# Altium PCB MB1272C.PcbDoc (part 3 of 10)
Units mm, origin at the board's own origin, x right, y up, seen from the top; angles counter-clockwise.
Board outline 101 x 71 mm, 6 copper layers (Top Layer, Signal Layer 1, Signal Layer 2, Signal Layer 3, Signal Layer 4, Bottom Layer), stack 1.552 mm thick; 520 components, 478 nets, 2156 pads, 1894 vias.

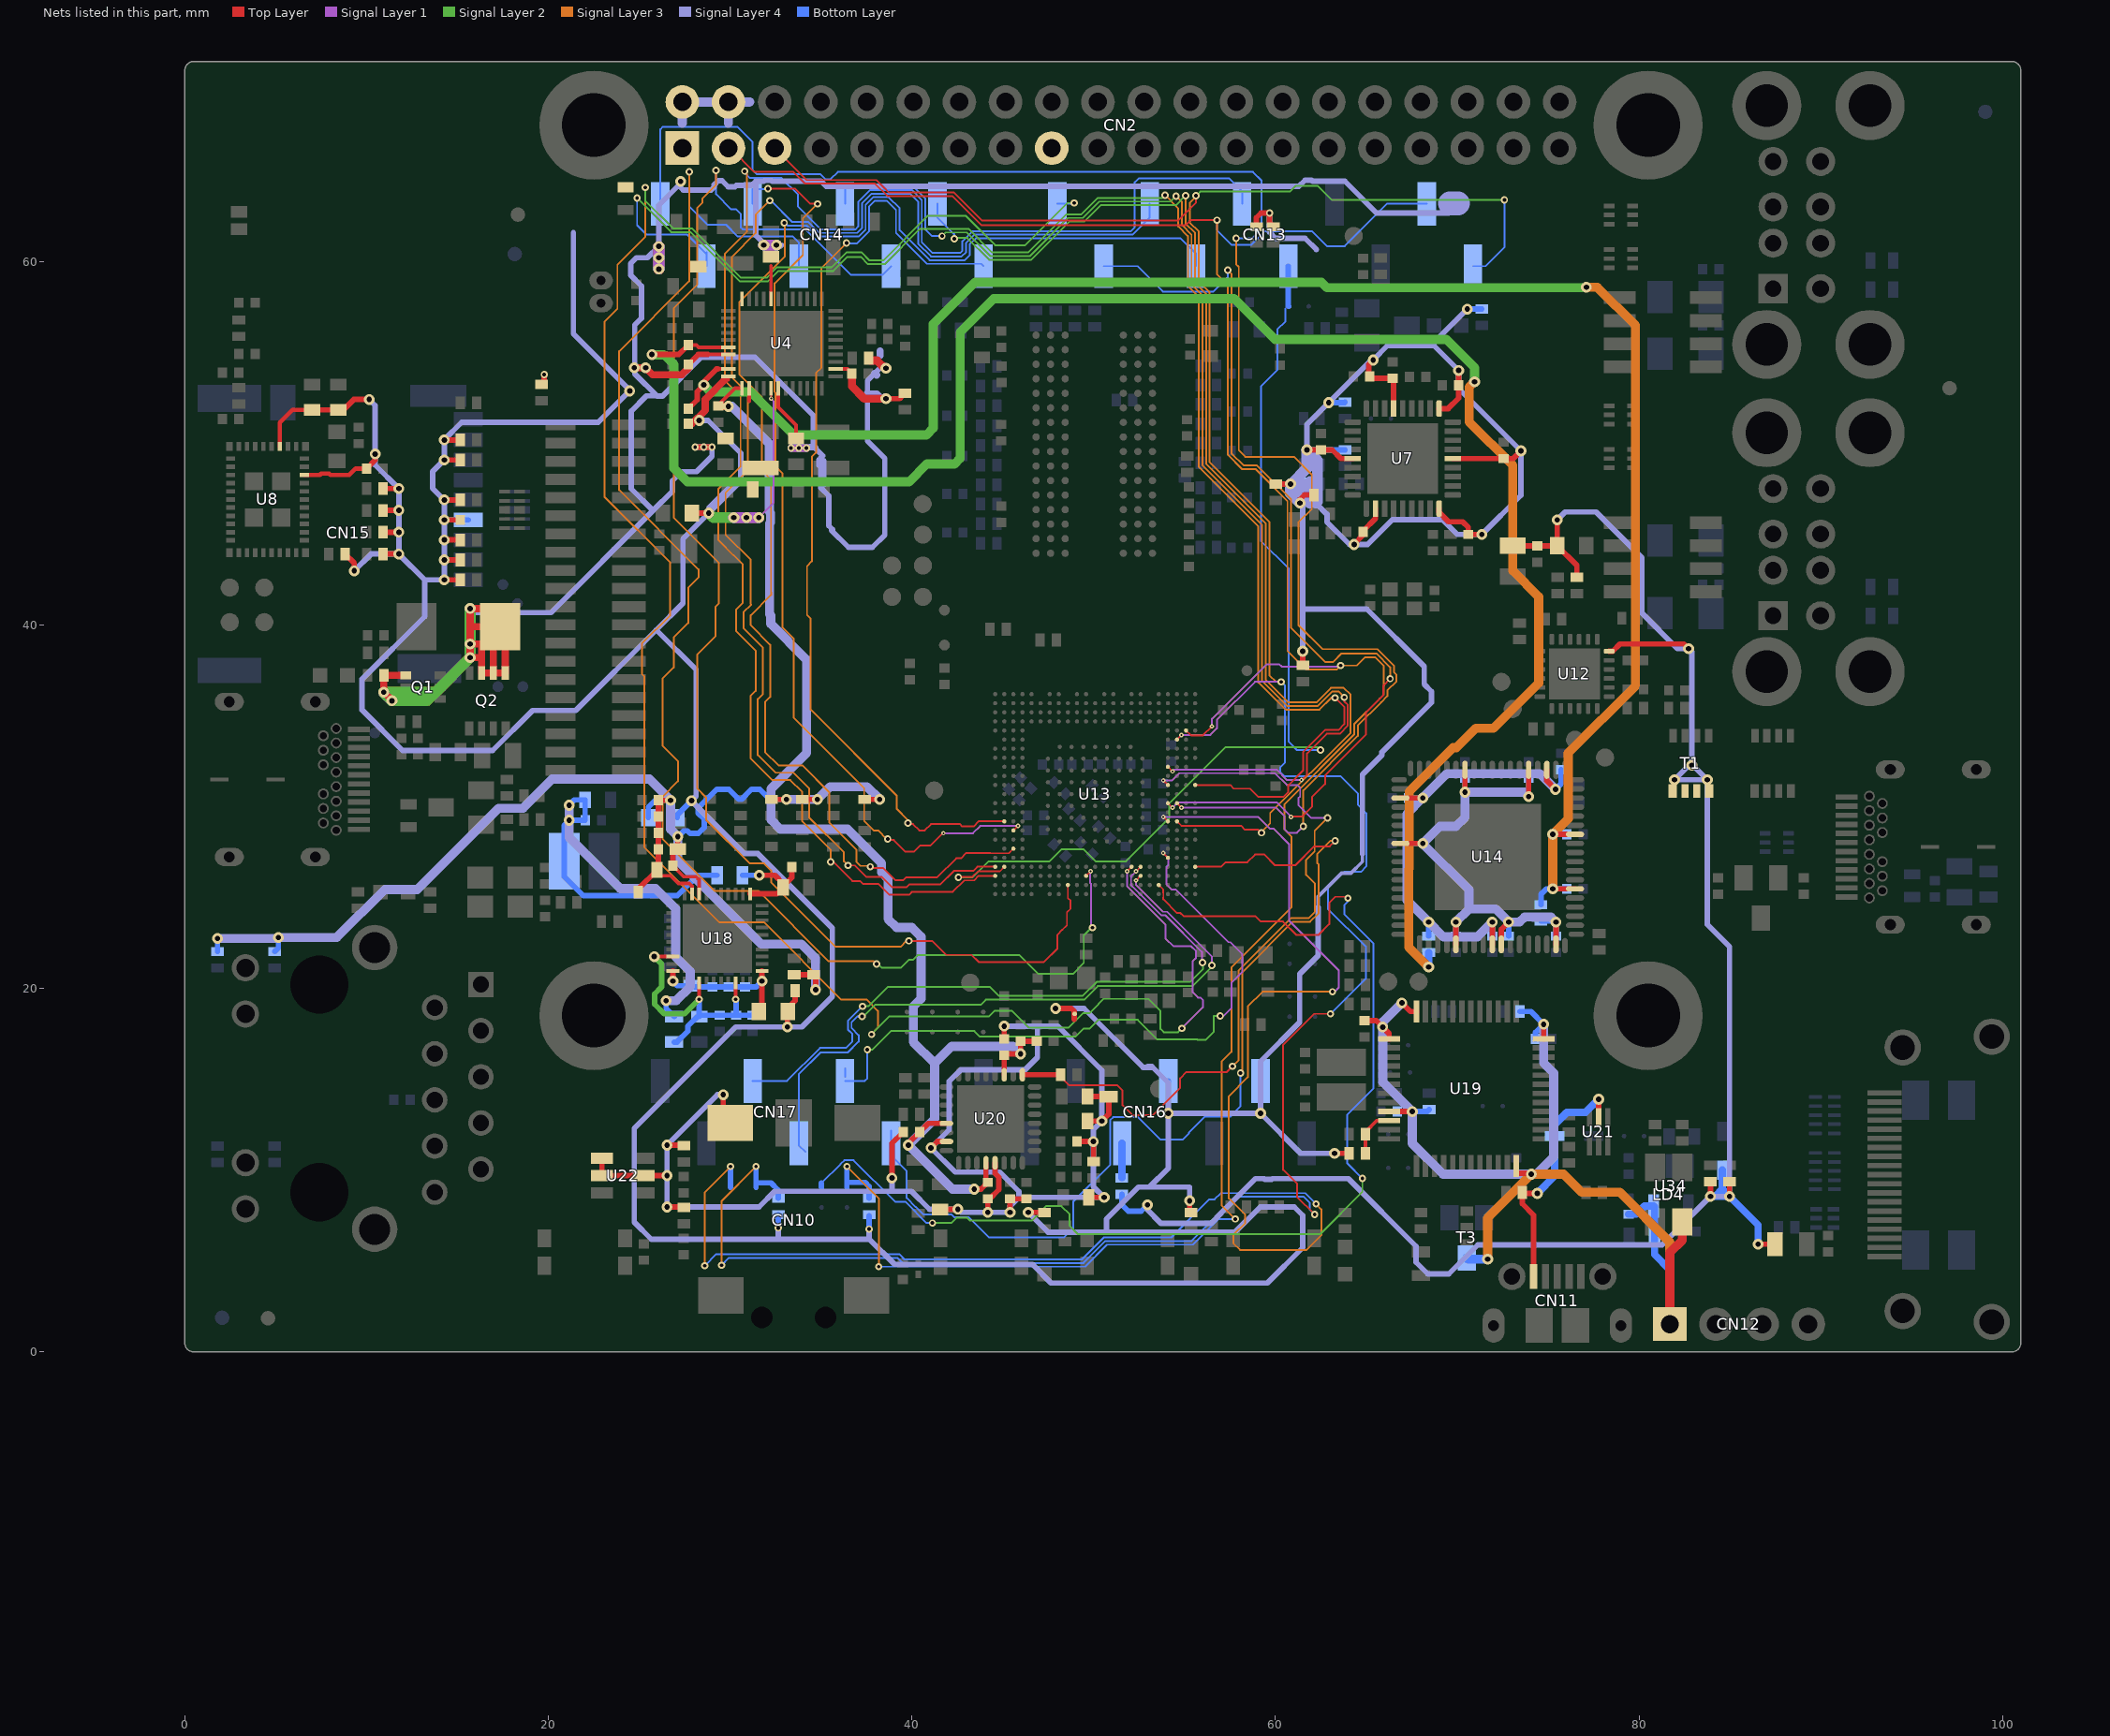
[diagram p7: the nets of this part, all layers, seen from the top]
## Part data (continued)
U7: library part MCD-00145, "USB HUB 2,0 Controller", Manufacturer=MICROCHIP
U8: library part MCD-00268, "IEEE802.11b/g/n W-LAN + Bluetooth 4.1+EDR module", Manufacturer=MURATA
U10 U26: library part MCD-00667, "4-line ESD protection for high speed lines", Manufacturer=STMICROELECTRONICS, Package=uQFN-10L
U12: library part MCD-00676, "USB Type-C controller with VCONN switch", Manufacturer=STMICROELECTRONICS, Manufacturer_Part_Number=STUSB1600AQTR
U13: library part MCD-00677, "MPU TFBGA12x12 secure boot+crypto", Manufacturer=STMICROELECTRONICS
U14: library part MCD-00267, "HDMI Transmitter, 72-pin 10 × 10 mm QFN", Manufacturer=LATTICE, Manufacturer_Part_Number=SiI9022ACNU
U15 U17: library part MCD-01125, "DUAL TRANSIL ARRAY FOR ESD PROTECTION", Manufacturer=STMICROELECTRONICS, Manufacturer_Part_Number=ESDA25L, Package=ESD_SOT23
U16 U23 U24 U25 U27 U28 U30: library part MCD-01026, "High power transient voltage suppressor", Manufacturer=STMICROELECTRONICS, Manufacturer_Part_Number=ESDA7P120-1U1M, Package=QFN1610
U18: library part MCD-01130, "10/100/1000M GIGABIT Ethernet Transceiver, QFN40 , SMPS version", Manufacturer=REALTEK
U19: library part MCD-00085, "Medium-density performance line ARM-based 32-bit MCU with 128KB Flash", Manufacturer=STMICROELECTRONICS, Manufacturer_Part_Number=STM32F103CBT6
U20: library part MCD-00265, "Low-Power, Stereo Codec with Headphone Amp", Manufacturer="CIRRUS LOGIC", Manufacturer_Part_Number=CS42L51-CNZ
U21: library part MCD-00169, "USB OTG FS ESD protection", Manufacturer=STMICROELECTRONICS, Manufacturer_Part_Number=USBLC6-2P6
U22: library part MCD-00247, "Quad Bidir ESD protection", Manufacturer=STMICROELECTRONICS, Manufacturer_Part_Number=ESDA6V1BC6
U31 U32: library part MCD-00297, "ESD protection & Common Filter High Speed serial Interfaces", Manufacturer=STMICROELECTRONICS, Manufacturer_Part_Number=ECMF04-4HSWM10
U33: library part MCD-01457, "ESD protection , 5 lines", Manufacturer=STMICROELECTRONICS, Package=QFN
U34: library part MCD-00086, "Ultra low drop-low noise BiCMOS voltage, regulators low ESR capacitors compatible", Manufacturer=STMICROELECTRONICS, Manufacturer_Part_Number=LD3985M33R
U35: library part MCD-00170, "ESD protection 6V1", Manufacturer=STMICROELECTRONICS, Manufacturer_Part_Number=ESDALC6V1-1U2
X1: library part MCD-01036, "Crystal 24MHz, 6pF, +-20ppm, 80ohms max, SMD", Manufacturer=NDK, Manufacturer_Part_Number="NX2016SA 24MHz EXS00A-CS10820", Package="(2016) 2.0 x 1.6 x 0.45 mm"
X2: library part MCD-01463, "Crystal 25Mhz, 10pF, -+50PPM, SMD", Manufacturer=NDK, Manufacturer_Part_Number="NX3225GA 25MHz EXS00A-CG06750", Package=3225
X4: library part MCD-01479, "Crystal 32.768kHz, 6pF, -+20PPM, R=80K, SMD", Manufacturer=NDK, Manufacturer_Part_Number="NX2012SA 32.768KHz EXS00A-MU00527", Package=NX2012SA
X5: library part MCD-00092, "Crystal 8Mhz, 8pF, -+50PPM, SMD", Manufacturer=NDK, Manufacturer_Part_Number="NX3225GD 8MHz EXS00A-CG04874"
X6: library part MCD-01627, "Oscillator 24Mhz, +-50ppm, Vcc:3.3V typ (1.62V min), square wave: [0.1Vcc;0.9Vcc], Enable pin", Manufacturer=NDK, Manufacturer_Part_Number="NZ2016SH 24MHz END4869F", Package=2.0x1.6x0.7mm

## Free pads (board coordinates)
  round 0.508 on Mech16: 1(25.738,-17.565) 1(74.585,-17.565)

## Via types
v1: diameter 0.4, hole 0.2, Top Layer to Bottom Layer, tented both sides, 912 vias
v2: diameter 0.25, hole 0.1, Top Layer to Signal Layer 1, tented top, 493 vias
v3: diameter 0.6, hole 0.3, Top Layer to Bottom Layer, tented both sides, 452 vias
v4: diameter 0.25, hole 0.1, Top Layer to Signal Layer 1, tented both sides, 37 vias

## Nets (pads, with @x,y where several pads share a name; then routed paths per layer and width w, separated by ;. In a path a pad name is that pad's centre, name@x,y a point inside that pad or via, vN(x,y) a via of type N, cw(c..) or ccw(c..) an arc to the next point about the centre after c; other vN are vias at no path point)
1V2_CVCC12: C141.2 C142.2 C164.2 C169.2 C170.2 C172.2 R152.1 U14.5 U14.12 U14.26 U14.42 U14.47 U14.53 | length 32.5
  Top Layer w0.3: U14.26@66.875,27.975 v3(68.1,27.975) ; U14.42@69.925,22.425 v3(69.925,23.65) ; v3(70.425,30.8) U14.12@70.425,32.025 ; U14.47@72.425,22.425 72.425,23.25 v3(72.825,23.65) ; U14.5@73.925,32.025 73.925,30.555 v3(73.929,30.551) v3@73.929,30.521 ; U14.53@75.425,22.425 v3(75.425,23.65)
  Signal Layer 4 w0.5: v3(69.925,23.65) 70.64,24.365 ; v3(73.929,30.551) 73.68,30.8 v3(70.425,30.8) 70.425,29.41 69.93,28.915 69.04,28.915 v3(68.1,27.975) 70.64,25.435 70.64,24.365 ; v3(75.425,23.65) 75.16,23.915 74.163,23.915 74.153,23.925 73.697,23.925 73.422,23.65 v3(72.825,23.65) 72.825,23.669 72.129,24.365 70.64,24.365
  Bottom Layer w0.3: C164.2@67.325,27.975 v3(68.1,27.975) ; C172.2@69.925,22.875 v3(69.925,23.65) ; v3(70.425,30.8) C142.2@70.425,31.575 ; C170.2@72.825,22.875 v3(72.825,23.65) ; C141.2@73.925,31.575 73.925,30.555 v3(73.929,30.551) ; R152.1@74.6,23.7 75.375,23.7 v3(75.425,23.65) C169.2@75.425,22.875
1V2_HDMI: C31.2 C160.2 C168.2 R152.2 U4.21 U14.60 U14.66 | length 104.9
  Top Layer w0.2: 29.325,54.075 U4.21@29.9,54.075
  Top Layer w0.3: C31.2@27.7,51.9 28.185,52.385 28.185,52.835 v3(28.55,53.2) 28.55,53.375 29.25,54.075 29.325,54.075 ; v3(75.25,25.475) U14.60@76.475,25.475 ; v3(75.25,28.475) U14.66@76.475,28.475
  Signal Layer 2 w0.5: v3(28.55,53.2) 28.925,52.825 31.125,52.825 33.5,50.45 40.8,50.45 41.175,50.825 41.175,56.55 43.475,58.85 62.525,58.85 62.825,58.55 77.075,58.55 v3(77.1,58.575)
  Signal Layer 3 w0.5: v3(75.25,25.475) v3(75.25,28.475) 76.1,29.325 76.1,32.95 79.8,36.65 79.8,56.475 77.7,58.575 v3(77.1,58.575)
  Signal Layer 4 w0.5: v3(75.25,25.475) v3(75.25,28.475)
  Bottom Layer w0.3: R152.2@74.6,24.6 74.6,25.175 74.9,25.475 v3(75.25,25.475) C168.2@76.025,25.475 ; v3(75.25,28.475) C160.2@76.025,28.475
1V05_AVDD_GMII: C177.2 C178.2 C179.2 C180.2 R160.1 U18.3 U18.8 U18.38 | length 15.7
  Top Layer w0.2: v3(25.825,21.75) U18.38@26.85,21.75 ; v1(28.3,19.4) U18.3@28.3,20.3 ; v1(30.3,19.4) U18.8@30.3,20.3
  Signal Layer 2 w0.3: v3(25.825,21.75) 26.225,21.35 26.225,20.075 25.85,19.7 25.85,19.125 26.375,18.6 27.5,18.6 v1(28.3,19.4)
  Bottom Layer w0.3: R160.1@26.925,17.05 27.075,17.05 27.675,17.65 27.675,17.925 28.2,18.45 C180.2@28.3,18.45 ; v1(28.3,19.4) C180.2@28.3,18.45 ; v1(30.3,19.4) 30.325,19.375 C178.2@30.325,18.525 ; C177.2@31.225,18.525 C178.2@30.325,18.525 ; C180.2@28.3,18.45 28.375,18.525 C179.2@29.425,18.525 C178.2@30.325,18.525
1V05_DVDD_GMII: C81.2 C85.2 R151.1 U18.21 | length 5.9
  Top Layer w0.3: U18.21@31.1,25.2 32.575,25.2 C85.2@32.925,25.55 C85.2@32.925,25.625 ; v3(31.6,26.225) 32.45,26.225 32.925,25.75 C85.2@32.925,25.625 ; C81.2@33.4,26.675 33.4,26.1 C85.2@32.925,25.625
  Bottom Layer w0.3: R151.1@30.675,26.225 v3(31.6,26.225)
1V05_GMII: C151.2 C157.2 LE1.2 R151.2 R160.2 | length 32.9
  Signal Layer 4 w0.5: v3(21.15,30.075) v3(21.15,29.25) 21.15,28.295 23.955,25.49 25.9,25.49 27.005,24.385 27.005,21.74 27.805,20.94 27.805,20.09 27.04,19.325 v3(26.475,19.325)
  Bottom Layer w0.3: v3(26.475,19.325) 26.475,18.9 R160.2@26.925,18.45 ; R151.2@29.275,26.225 28.225,26.225 27.1,25.1 21.925,25.1 20.875,26.15 LE1.2@20.875,27 20.875,28.975 v3(21.15,29.25) ; v3(21.15,29.25) v3(21.15,30.075) 21.15,30.1 21.425,30.375 C151.2@22.025,30.375 C157.2@22.025,29.25 v3(21.15,29.25)
1V8_AUDIO: C33.2 C94.2 C95.2 C97.2 C102.2 C107.2 U4.23 U20.5 U20.12 U20.27 | length 71.1
  Top Layer w0.2: C33.2@29.35,52.05 29.35,52.1 30.275,53.025 U4.23@30.65,53.025
  Top Layer w0.3: v3@29.675,52 v3@29.675,52.025 ; v3@29.725,52.025 29.75,52 29.775,52.025 v3(29.9,52.025) ; v3(39.8,11.375) 39.9,11.375 39.9,11.575 C102.2@40.425,12.1 40.9,12.575 U20.5@41.9,12.575 ; v3(43.425,8.95) 43.8,8.95 C107.2@44.175,9.325 44.075,9.425 U20.12@44.075,10.4 ; U20.27@45.075,15.25 C97.2@45.075,16.325 45.15,16.4 v3(45.975,16.4) C94.2@45.975,17.1 C95.2@46.875,17.1
  Top Layer w0.4: v3@29.675,52.025 29.725,52.025 v3@29.775,52.025
  Signal Layer 4 w0.5: v3(29.9,52.025) 30.1,52.025 32.16,49.965 32.16,46.234 32.225,46.169 32.225,45.631 32.175,45.581 32.175,40.573 32.23,40.518 32.23,40.062 34.205,38.087 34.205,32.94 32.255,30.99 32.255,29.265 32.755,28.765 36.455,28.765 38.33,26.89 38.33,26.39 38.68,26.04 38.68,23.825 39.155,23.35 40,23.35 40.505,22.845 40.505,19.43 40.078,19.003 40.078,17.05 41.25,15.878 ; v3(43.425,8.95) 42.225,8.95 v3(39.8,11.375) 41.25,12.825 41.25,15.878 ; v3(45.975,16.4) 45.56,16.815 42.187,16.815 41.25,15.878
3V3: C21.2 C23.2 C28.2 C29.2 C30.2 C38.2 C39.2 C40.2 C42.2 C45.2 C49.2 C50.2 C54.2 CN2.1 CN2.17 CN15.4 CN16.2 CN16.4 L5.2 L7.1 L10.2 L11.2 R1.1 R2.1 R11.1 R14.2 R16.2 R17.1 R18.2 R19.2 R20.1 R22.1 R25.2 R26.1 R27.1 R28.2 R33.2 R40.1 R94.1 R105.2 R106.2 R114.2 R127.2 R134.2 R140.2 R166.1 R167.1 R300.1 R600.1 SB5.1 U4.22 U4.27 U7.5 U7.10 U7.15 U7.23 U7.29 U7.36 U8.30 U8.36 | length 408.7
  Top Layer w0.1: v2(32.25,52.45) U4.27@32.25,53.025
  Top Layer w0.2: 29.725,53.5 U4.22@29.9,53.675 29.9,53.491
  Top Layer w0.25: U8.36@5.225,49.825 5.225,51.125 5.925,51.825 C28.2@7,51.825 ; U8.30@6.575,48.25 7.433,48.25 7.508,48.325 7.942,48.325 8.017,48.25 9.05,48.25 9.4,48.6 C45.2@10,48.6
  Top Layer w0.3: C28.2@7,51.825 C29.2@8.45,51.825 8.725,51.825 9.3,52.4 v3(10.15,52.4) ; R26.1@8.825,43.9 9.325,43.4 v3(9.325,42.975) ; C45.2@10,48.6 10.475,49.075 v3(10.475,49.4) ; R27.1@10.9,43.9 v3(11.775,43.9) ; R22.1@10.9,45.1 v3(11.775,45.1) ; R20.1@10.9,46.3 v3(11.775,46.3) ; R17.1@10.9,47.5 v3(11.775,47.5) ; v3@14.25,45.775 C49.2@15.15,45.775 ; v3(14.275,42.475) R33.2@15.15,42.475 ; v3(14.275,43.575) R28.2@15.15,43.575 ; v3(14.275,44.675) R25.2@15.15,44.675 ; v3(14.275,46.875) R19.2@15.15,46.875 ; v3(14.275,49.075) R16.2@15.15,49.075 ; v3(14.275,50.175) R14.2@15.15,50.175 ; R11.1@19.625,53.225 19.775,53.375 v1(19.775,53.775) ; L7.1@27.9,46.15 v3(28.825,46.15) ; 29.625,53.5 29.725,53.5 ; v3(33.15,17.875) 33.15,18.9 33.575,19.325 R300.1@33.575,19.75 ; v3(46.4,7.675) R105.2@47.3,7.675 ; v3(47.9,18.9) 48.775,18.9 48.925,18.75 48.925,18.3 ; v3(55.28,8.315) 55.28,7.745 R106.2@55.35,7.675 ; R1.1@58.95,61.9 58.95,62.4 59.205,62.655 v1(59.675,62.655) 59.675,62.1 R2.1@59.875,61.9 ; R600.1@60.006,47.75 v3(60.825,47.75) ; v3(61.35,46.7) 61.35,46.9 61.6,47.15 R18.2@62.125,47.15 ; R40.1@61.5,37.775 v3(61.5,38.55) ; v3(61.725,49.625) C38.2@62.5,49.625 63.125,49.625 63.6,49.15 U7.23@64.25,49.15 ; v3(63.25,10.925) R94.1@64.05,10.925 ; v3(64.325,44.425) 64.325,44.45 64.825,44.95 C50.2@64.825,45.125 64.825,45.175 65.5,45.85 U7.29@65.5,46.4 ; v3(65.375,54.575) 65.125,54.325 65.125,53.775 65.325,53.575 C21.2@66.45,53.575 66.5,53.525 U7.15@66.5,51.9 ; U7.36@69,46.4 69,46.2 69.525,45.675 70.3,45.675 70.6,45.375 C54.2@70.6,44.975 v3(71.35,44.975) ; U7.10@69,51.9 69.5,51.9 70.075,52.475 C30.2@70.075,53.175 v3(70.075,54) ; U7.5@69.75,49.15 C40.2@72.55,49.15 73.075,49.15 v3(73.5,49.575)
  Top Layer w0.4: C39.2@27.7,51.075 27.9,51.075 28.635,51.81 28.635,52.41 29.725,53.5
  Signal Layer 1 w0.1: v3(31.575,45.9) 32.4,46.725 32.4,52.3 v2(32.25,52.45)
  Signal Layer 1 w0.6: v3(30.2,45.9) v3(30.9,45.9) v3(31.575,45.9)
  Signal Layer 2 w0.6: v3(28.825,46.15) 29.075,45.9 v3(30.2,45.9) v3(30.9,45.9) v3(31.575,45.9)
  Signal Layer 3 w0.6: v3(30.2,45.9) v3(30.9,45.9) v3(31.575,45.9)
  Signal Layer 4 w0.2: 62.355,24.455 62.355,25.056 63.639,26.34 64.15,26.34 64.78,26.97 64.78,27.39
  Signal Layer 4 w0.3: v3(9.325,42.975) 10.25,43.9 v3(11.775,43.9) ; v3(10.15,52.4) 10.475,52.075 v3(10.475,49.4) 10.475,48.8 v3(11.775,47.5) v3(11.775,46.3) v3(11.775,45.1) v3(11.775,43.9) ; 21.38,61.58 21.38,56.02 24.475,52.925 v3(24.475,52.875) 22.74,51.14 15.24,51.14 v3(14.275,50.175) v3(14.275,49.075) 13.63,48.43 13.63,47.52 v3(14.275,46.875) v3(14.275,45.775) v3(14.275,44.675) v3(14.275,43.575) v3(14.275,42.475) 13.2,42.475 ; v3(28.3,51.25) 28.786,51.25 30.59,49.446 30.59,47.915 v3(28.825,46.15) ; 29.9,47.5 28.825,46.425 v3(28.825,46.15) ; v3(31.575,45.9) 31.55,45.925 29.155,45.925 29.027,46.052 28.975,46 v3(28.825,46.15) ; v1(32.65,6.825) 32.65,6.2 ; v1(37.65,6.755) 37.65,6.21 ; v3(46.4,7.675) 47.485,6.59 49.98,6.59 50.68,6.59 ; v3(47.9,18.9) 49.47,18.9 52.72,15.65 53.15,15.65 53.2,15.7 ; 52.964,15.7 53.2,15.7 ; v3(55.28,8.315) 55.28,9.045 55.26,9.065 53.06,9.065 ; v1(59.675,62.655) 59.675,61.6 60,61.275 61.625,61.275 62.25,60.65 ; v3(61.5,38.55) 61.5,40.99 ; v3(61.725,49.625) 61.725,51.025 v3(62.925,52.225) 65.275,54.575 v3(65.375,54.575) 66.165,55.365 68.71,55.365 ; 62.355,24.455 62.355,21.815 61.33,20.79 61.33,18.14 59.18,15.99 v3(59.18,13.125) ; v3(63.25,10.925) 61.38,10.925 v3(59.18,13.125) ; 64.78,27.39 64.78,31.765 65.857,32.842 65.857,33.004 68.58,35.726 68.58,36.34 68.18,36.74 68.18,37.715 65.03,40.865 61.625,40.865 61.5,40.99 ; v3(70.55,57.375) 68.71,55.535 68.71,55.365 ; v3(11.775,43.9) 13.2,42.475 ; 13.2,42.475 13.2,40.46 9.755,37.015 9.755,35.315 11.98,33.09 16.93,33.09 19.13,35.29 21.505,35.29 25.93,39.715 ; 25.93,39.715 27.405,41.19 27.405,44.73 v3(28.825,46.15) ; 25.93,39.715 25.955,39.715 28.13,37.54 28.13,30.58 v3(27.875,30.325) 30.785,27.415 31.53,27.415 35.625,23.32 35.625,19.55 33.95,17.875 v3(33.15,17.875) 30.315,17.875 30.308,17.883 24.73,12.305 24.73,7.14 25.67,6.2 32.65,6.2 ; 32.65,6.2 37.65,6.2 37.65,6.21 ; 37.65,6.21 39.045,4.815 46.63,4.815 47.655,3.79 59.555,3.79 61.5,5.735 61.5,7.511 61.036,7.975 59.165,7.975 57.78,6.59 50.68,6.59 ; 50.68,6.59 50.697,6.607 50.697,7.307 52.455,9.065 53.06,9.065 ; 53.06,9.065 54.1,10.105 v3(54.1,13.125) ; 53.2,15.7 54.1,14.8 v3(54.1,13.125) ; v3(54.1,13.125) v3(59.18,13.125) ; 61.5,40.99 61.5,46.55 v3(61.35,46.7) 61.875,46.7 62.22,46.7 62.83,46.09 62.83,45.665 64.07,44.425 v3(64.325,44.425) 65.065,44.425 66.43,45.79 69.18,45.79 69.995,44.975 v3(71.35,44.975) 73.5,47.125 v3(73.5,49.575) 73.497,49.575 70.075,52.997 v3(70.075,54) 68.71,55.365
  Signal Layer 4 w0.6: v3@60.85,47.7 61.25,47.3 61.275,47.3 ; v3(61.35,46.7) 60.825,47.225 v3(60.825,47.75) v3@60.85,47.725 ; 61.875,46.7 61.275,47.3 ; 62.22,46.7 62.3,46.78 62.3,49.05 v3(61.725,49.625) 61.725,48.6 v3@60.85,47.725 ; v3@60.85,47.725 61.275,47.3 ; v3@60.85,47.725 61.75,47.725 61.9,47.875 61.9,47.3 61.275,47.3
  Bottom Layer w0.3: v3(14.275,45.775) CN15.4@15.6,45.775 ; L11.2@27.1,29.4 27.1,29.55 v3(27.875,30.325) ; v1(32.65,6.825) R167.1@32.65,7.55 ; v1(37.65,6.755) R166.1@37.65,7.48 ; v3(54.1,13.125) CN16.4@54.1,14.904 ; v3(59.18,13.125) CN16.2@59.18,14.904 ; v3(60.825,47.75) R140.2@61.55,47.75 ; v3(61.725,49.625) R134.2@63.825,49.625 ; v3(62.925,52.225) 63.8,52.225 R127.2@63.825,52.25 ; v3(70.55,57.375) R114.2@71.35,57.375
  Bottom Layer w0.6: v3(30.2,45.9) v3(30.9,45.9) v3(31.575,45.9)
3V3_AVDD_GMII: C173.2 C174.2 C175.2 C176.2 L10.1 U18.11 U18.40 | length 7.8
  Top Layer w0.3: v3(26.85,20.4) U18.40@26.85,20.95 ; L10.1@31.75,18.9 v3(31.75,20.4) U18.11@31.75,20.95
  Bottom Layer w0.3: v3(26.85,20.4) 27.1,20.15 C173.2@27.9,20.15 27.975,20.075 C176.2@29.025,20.075 C175.2@29.925,20.075 C174.2@30.825,20.075 31.425,20.075 v3(31.75,20.4)
3V3_DVDD_GMII: C74.2 C75.2 C76.1 C77.2 C78.2 C79.2 C80.2 L11.1 R52.2 R53.2 R55.2 R65.2 R75.2 R76.2 R156.1 R157.2 U18.28 U18.29 | length 80.1
  Top Layer w0.2: C80.2@25.975,26.525 25.975,26.5 25.975,26.275 26.05,26.2 26.725,26.2 27.15,25.775 27.75,25.775 27.9,25.625 U18.29@27.9,25.2 ; C79.2@26.8,26.7 C79.2@26.85,26.75 27.45,26.15 28.125,26.15 28.3,25.975 U18.28@28.3,25.2
  Top Layer w0.3: R65.2@24.95,25.3 24.95,25.475 C80.2@25.975,26.5 ; C80.2@25.975,26.525 26.05,26.6 C78.2@26.05,27.65 C77.2@26.05,28.55 C75.2@26.05,29.45 C74.2@26.05,30.35 v3(26.725,30.35) ; C79.2@26.85,26.75 26.85,27.4 C76.1@27.125,27.675 27.125,28.35 v3(27.126,28.351) ; R52.2@32.275,30.4 v3(33.1,30.4) ; R75.2@33.525,20.75 R76.2@34.6,20.75 34.58,20.73 34.7,20.61 v3(34.7,19.925) ; R53.2@33.975,30.4 v3(34.8,30.4) ; R55.2@37.4,30.4 v3(38.225,30.4)
  Signal Layer 4 w0.5: v3(1.8,22.75) 5.1,22.75 v3(5.15,22.8) 8.365,22.8 11.005,25.44 12.79,25.44 17.265,29.915 18.605,29.915 20.205,31.515 25.56,31.515 v3(26.725,30.35) 26.725,28.753 v3(27.126,28.351) 27.126,27.019 31.705,22.44 33.91,22.44 34.7,21.65 v3(34.7,19.925) ; v3(33.1,30.4) v3(34.8,30.4) 35.5,31.1 37.525,31.1 v3(38.225,30.4)
  Bottom Layer w0.3: R157.2@1.8,22.025 v3(1.8,22.75) ; R156.1@4.95,22.025 5.15,22.225 v3(5.15,22.8) ; L11.1@25.5,29.4 25.5,29.975 25.875,30.35 v3(26.725,30.35) ; v3(27.126,28.351) 27.45,28.675 27.647,28.675 27.797,28.525 28.253,28.525 28.575,28.847 28.575,29.303 28.227,29.651 28.227,29.899 28.425,30.097 28.425,30.11 29.265,30.95 29.928,30.95 30.478,30.4 30.622,30.4 31.172,30.95 31.628,30.95 32.178,30.4 v3(33.1,30.4)
3V3_HDMI: C20.2 R154.2 U4.18 | length 105.8
  Top Layer w0.2: C20.2@27.7,55.4 28.15,55.4 28.275,55.275 U4.18@29.9,55.275
  Top Layer w0.3: v3(25.7,54.875) 27.175,54.875 C20.2@27.7,55.4 C20.2@27.7,55.275
  Signal Layer 2 w0.5: v3(25.7,54.875) 25.847,54.875 25.872,54.85 26.328,54.85 26.353,54.875 26.9,54.328 26.9,52.6 ; 26.9,52.869 26.9,52.6 ; v3(70.95,53.375) 70.95,54.147 69.397,55.7 59.975,55.7 57.725,57.95 44.5,57.95 42.65,56.1 42.65,49.15 42.35,48.85 40.825,48.85 39.85,47.875 27.647,47.875 26.9,48.622 26.9,52.6
  Signal Layer 3 w0.5: v3(68.425,21.175) 67.325,22.275 67.325,26.561 67.35,26.586 67.35,30.825 69.765,33.24 69.944,33.24 71.019,34.315 72,34.315 74.475,36.79 74.475,41.55 73.05,42.975 73.05,48.775 70.65,51.175 70.65,53.075 v3(70.95,53.375)
  Bottom Layer w0.4: v3(68.425,21.175) R154.2@68.425,21.975
3V3_IOVCC: C140.2 C154.2 C171.2 R154.1 U14.3 U14.21 U14.46 | length 27.3
  Top Layer w0.3: U14.21@66.875,30.475 v3(68.1,30.475) ; U14.46@71.925,22.425 v3(71.925,23.65) ; U14.3@74.925,32.025 74.925,31.425 v3(75.4,30.95)
  Signal Layer 4 w0.5: v3(71.925,23.65) 71.115,22.84 69.235,22.84 v3(68.425,23.65) 67.23,24.845 67.23,29.605 v3(68.1,30.475) 69.44,31.815 74.535,31.815 v3(75.4,30.95)
  Bottom Layer w0.3: C154.2@67.325,30.475 v3(68.1,30.475) ; R154.1@68.425,22.875 v3(68.425,23.65) ; C171.2@71.925,22.875 v3(71.925,23.65) ; v3(75.4,30.95) 75.7,31.25 C140.2@75.7,32.025
3V3_ST_LINK: C93.2 C181.2 C184.2 C186.2 C188.2 C190.2 CN12.1 LD4.4 R158.2 R161.2 T3.3 U19.1 U19.9 U19.24 U19.36 U19.48 U34.5 | length 71.8
  Top Layer w0.3: C93.2@64.9,18.225 65.545,18.225 v3(65.898,17.872) 66.25,17.52 U19.1@66.25,17.225 ; U19.9@66.25,13.225 v3(67.525,13.225) ; v3(66.95,19.2) 67.425,18.725 U19.48@67.75,18.725 ; U19.24@73.25,10.225 73.25,9.825 74.025,9.825 v3(74.075,9.775) ; U19.36@74.75,17.225 v3(74.75,18.025)
  Top Layer w0.5: CN12.1@81.69,1.525 81.69,5.465 82.375,6.15 LD4.4@82.375,7.15
  Signal Layer 3 w0.5: v3(71.675,5.1) 71.675,7.375 v3(74.075,9.775) 75.845,9.775 76.83,8.79 78.93,8.79 81.69,6.03 CN12.1@81.69,1.525
  Signal Layer 4 w0.5: v3(65.898,17.872) 65.898,18.147 v3@65.905,18.155 ; v3(66.95,19.2) v3@65.905,18.155 ; v3(74.75,18.025) 74.75,15.895 75.305,15.34 75.305,10.74 74.34,9.775 v3(74.075,9.775) 69.215,9.775 67.525,11.465 v3(67.525,13.225) 65.905,14.845 v3@65.905,18.155
  Bottom Layer w0.3: C184.2@66.7,13.225 v3(67.525,13.225) 68.35,13.225 R161.2@68.45,13.325 ; C186.2@73.25,9.775 v3(74.075,9.775) ; R158.2@73.45,18.725 74.05,18.725 v3(74.75,18.025) 74.3,17.575 C181.2@74.3,17.225
  Bottom Layer w0.4: C188.2@79.425,7.575 79.85,7.575 80.3,8.025 U34.5@80.8,8.025 80.85,7.975 C190.2@80.85,6.4 80.85,5.365 81.69,4.525 CN12.1@81.69,1.525
  Bottom Layer w0.5: T3.3@70.525,5.175 70.6,5.1 v3(71.675,5.1)
5V: CN16.5 R165.2 | length 1.9
  Bottom Layer w0.3: R165.2@51.55,9.575 R165.2@51.56,9.585
  Bottom Layer w0.4: R165.2@51.56,9.585 CN16.5@51.56,11.475
5V_USB_ST_LINK: CN11.1 D2.1 R99.1 U21.5 | length 13.9
  Top Layer w0.3: CN11.1@74.2,4.15 74.2,7.525 73.575,8.15 R99.1@73.575,8.775 73.625,8.725 v3(74.4,8.725) ; U21.5@77.775,12.905 v3(77.775,13.9)
  Bottom Layer w0.4: v3(74.4,8.725) 75.355,9.68 D2.1@75.355,11.875 75.355,12.505 76.025,13.175 77.05,13.175 v3(77.775,13.9)
5V_VIN: C4.2 C5.2 C26.2 C27.2 C41.2 C43.2 C55.2 C56.2 C60.1 CN2.2 CN2.4 D1.1 F1.1 L8.1 Q1.4 Q2.1 Q2.2 Q2.3 R9.1 R12.2 R32.2 R41.2 R97.2 R98.2 R165.1 T1.5 T1.6 T1.7 T1.8 U4.8 U4.12 U4.19 U4.24 U4.28 U4.36 U12.24 U23.1 | length 332.1
  Top Layer w0.2: 28.775,54.875 U4.19@29.9,54.875 ; 31.05,52.3 U4.24@31.05,53.025 ; U4.8@32.25,57.925 32.25,59.76 ; U4.28@32.65,53.025 32.65,51.975 33.625,51 C43.2@33.625,50.25 ; U4.36@35.8,54.075 36.45,54.075 C26.2@36.7,53.825
  Top Layer w0.3: C27.2@27.7,54.325 28.25,54.875 28.775,54.875 ; v1(28.075,49.775) v1(28.55,49.775) v1(29,49.775) ; v3(38.575,52.45) 39.325,52.45 R12.2@39.461,52.586 ; C55.2@73.05,44.35 C56.2@74.4,44.35 L8.1@75.5,44.35 ; v3(75.5,45.775) L8.1@75.5,44.35 ; R32.2@76.575,42.625 76.575,43.275 L8.1@75.5,44.35 ; U12.24@78.35,38.55 78.55,38.55 78.95,38.95 82.47,38.95 v3(82.725,38.695) ; v3(83.925,8.55) R97.2@83.925,9.375 ; v3(84.975,8.55) R98.2@84.975,9.375 ; v3(86.55,5.925) F1.1@87.425,5.925 ; F1.1@87.475,5.975 F1.1@87.425,5.925 ; F1.1@87.5,5.95 F1.1@87.475,5.925 F1.1@87.425,5.925
  Top Layer w0.4: v3(11.4,35.825) 11.4,35.85 v3(10.95,36.3) R41.2@10.95,37.225 Q1.4@12.15,37.225 ; v3(24.725,54.15) v3(25.35,54.15) 25.735,53.765 27.335,53.765 27.7,54.13 C27.2@27.7,54.325 ; v3(15.7,38.95) v3(15.7,38.2) 16.325,38.2 ; v3(15.7,38.95) 15.7,39.9 ; v3(15.7,38.95) C60.1@16.4,38.95 ; 15.7,39.9 v3(15.7,40.9) ; 15.7,39.9 C60.1@17.35,39.9 ; v3(15.7,40.9) 17.35,40.9 C60.1@17.35,39.9 ; v3(15.7,40.9) 15.675,40.9 v3(15.7,40.9) ; 16.325,38.2 16.325,38.875 C60.1@16.4,38.95 ; 16.325,38.2 Q2.3@16.325,37.35 Q2.2@16.975,37.35 ; C60.1@16.4,38.95 C60.1@16.975,39.525 ; Q2.2@16.975,37.35 Q2.1@17.625,37.35 17.625,39.625 C60.1@17.35,39.9 ; Q2.2@16.975,37.35 C60.1@16.975,39.525 ; C60.1@16.975,39.525 C60.1@17.35,39.9
  Top Layer w0.45: C26.2@36.7,53.825 36.7,53.127 37.377,52.45 v3(38.575,52.45) ; R9.1@37.625,54.675 37.75,54.55 38.078,54.55 38.503,54.125 v3(38.575,54.125)
  Signal Layer 1 w0.3: v3(24.725,54.15) v3(25.35,54.15) ; v1(28.075,49.775) v1(28.55,49.775) v1(29,49.775)
  Signal Layer 1 w0.4: v1(33.35,49.725) v1(33.775,49.725) v1(34.2,49.725)
  Signal Layer 1 w0.6: v3(26.075,59.575) v3(26.075,60.2) v3(26.075,60.825) ; v3(31.85,60.9) v3(32.55,60.9)
  Signal Layer 2 w0.3: v3(24.725,54.15) v3(25.35,54.15) ; v1(28.075,49.775) v1(28.55,49.775) v1(29,49.775)
  Signal Layer 2 w0.4: v1(33.35,49.725) v1(33.775,49.725) 34.025,49.725 v1@34.05,49.75
  Signal Layer 2 w0.6: v3(15.7,40.9) v3(15.7,38.95) v3(15.7,38.2) 13.8,36.3 ; v3(26.075,59.575) v3(26.075,60.2) v3(26.075,60.825) ; v3(31.85,60.9) v3(32.55,60.9) ; 13.8,36.3 v3(10.95,36.3) 10.95,36.275 v3(11.4,35.825) 13.325,35.825 13.8,36.3
  Signal Layer 3 w0.3: v3(24.725,54.15) v3(25.35,54.15) ; v1(28.075,49.775) v1(28.55,49.775) v1(29,49.775)
  Signal Layer 3 w0.4: v1(33.35,49.725) v1(33.775,49.725) v1(34.2,49.725)
  Signal Layer 3 w0.6: v3(15.7,40.9) v3(15.7,38.95) v3(15.7,38.2) 13.8,36.3 ; v3(26.075,59.575) v3(26.075,60.2) v3(26.075,60.825) ; v3(31.85,60.9) v3(32.55,60.9) ; 13.8,36.3 v3(10.95,36.3) 10.95,36.275 v3(11.4,35.825) 13.325,35.825 13.8,36.3
  Signal Layer 4 w0.3: v3(10.95,36.3) 13.85,36.3 15.7,38.15 v3(15.7,38.2) v3(15.7,38.95) v3(15.7,40.9) 15.925,40.675 20.15,40.675 25.76,46.285 ; v3(24.725,54.15) v3@24.755,54.15 ; v3(25.35,54.15) v3@24.755,54.15 ; v3(26.075,59.575) v3(26.075,60.2) v3(26.075,60.825) ; v1(28.075,49.775) v1(28.55,49.775) v1(29,49.775) 29,49.275 28.15,48.425 27.322,48.425 26.825,47.928 26.825,47.35 25.76,46.285 ; v3(31.85,60.9) v3@31.945,60.9 ; v3@32.75,60.825 32.825,60.9 v3(32.55,60.9) v3@31.945,60.9 ; v1(33.35,49.725) v1(33.775,49.725) v1(34.2,49.725) 34.301,49.725 v1@34.326,49.75 ; v1@34.35,49.75 v1@34.326,49.75 ; 34.887,49.088 34.887,48.763 35.15,49.026 ; 34.95,49.15 34.988,49.188 ; 34.975,48.675 34.975,47.553 ; v3@38.525,52.6 38.575,52.55 v3(38.575,52.45) 38.375,52.45 38.075,52.75 37.55,52.75 ; v3(38.575,54.125) 38.24,54.125 37.958,53.843 37.55,53.435 37.55,52.75 ; v3(52.955,8.09) 52.955,7.865 52.93,7.84 53.705,7.065 56.443,7.065 57.025,7.647 57.025,7.66 58.9,9.535 59.374,9.535 59.414,9.495 59.786,9.495 59.826,9.535 64.01,9.535 67.73,5.815 67.73,4.94 68.38,4.29 69.53,4.29 71.13,5.89 81.265,5.89 v3(83.925,8.55) v3(84.975,8.55) 84.975,22.295 83.75,23.52 v3(83.75,31.475) ; 70.05,63.19 69.525,62.665 65.56,62.665 63.81,64.415 62.044,64.415 61.992,64.467 61.619,64.467 61.278,64.125 35.289,64.125 34.999,64.415 32.306,64.415 32.266,64.454 31.894,64.454 31.854,64.415 31.405,64.415 ; v3(75.5,45.775) 75.938,46.213 77.632,46.213 80.155,43.69 80.155,40.645 82.105,38.695 v3(82.725,38.695) 82.9,38.52 v3(82.9,32.275) ; v3@24.755,54.15 24.755,56.502 25.125,56.872 25.125,58.647 24.525,59.247 24.525,59.878 24.847,60.2 25.45,60.2 v3(26.075,60.825) ; v3@24.755,54.15 24.755,53.815 25.97,52.6 ; 25.76,46.285 24.555,47.49 24.555,51.758 25.397,52.6 25.97,52.6 ; 25.97,52.6 26.17,52.6 26.193,52.578 ; 25.97,52.6 25.992,52.578 26.193,52.578 ; v3(26.075,60.825) 26.075,63.085 27.165,64.175 27.415,63.925 28.95,63.925 29.126,64.101 29.126,64.214 29.351,64.44 29.554,64.44 29.894,64.1 30.266,64.1 30.341,64.175 31.165,64.175 31.405,64.415 ; 26.193,52.578 26.278,52.578 28.425,54.725 31.375,54.725 34.58,51.52 34.58,49.8 ; 31.405,64.415 31.405,61.44 v3@31.945,60.9 ; v1@34.326,49.75 v1@34.376,49.8 ; v1@34.376,49.8 34.58,49.8 ; v1@34.376,49.8 34.426,49.75 34.55,49.75 ; 34.55,49.75 34.6,49.8 ; 34.55,49.75 34.65,49.75 ; 34.58,49.8 34.6,49.8 ; 34.6,49.8 34.65,49.75 ; 34.65,49.75 34.663,49.737 34.688,49.713 ; 34.65,49.75 34.725,49.75 34.688,49.713 ; 34.688,49.713 35.1,49.3 34.988,49.188 ; 34.975,47.553 35.15,47.728 35.15,49.026 ; 34.975,47.553 35.425,47.103 35.425,45.455 35.63,45.25 35.575,45.195 36.505,44.265 37.83,44.265 38.505,44.94 38.505,49.165 37.55,50.12 37.55,52.75 ; 34.988,49.188 35.15,49.026 ; v3(82.9,32.275) 82.75,32.275 v3(81.95,31.475) v3(83.75,31.475) ; v3(82.9,32.275) 82.95,32.275 v3(83.75,31.475)
  Signal Layer 4 w0.4: 37.55,52.75 37.85,52.45 v3@38.375,52.45 ; 37.958,53.843 38.05,53.75 ; 38.25,54.826 38.25,55.075
  Signal Layer 4 w0.5: 27.375,67.605 27.37,67.61 CN2.2@27.37,68.77 CN2.4@29.91,68.77 ; 29.9,67.605 29.91,67.615 CN2.4@29.91,68.77 ; 31.075,68.775 31.07,68.77 CN2.4@29.91,68.77
  Signal Layer 4 w1.3: 69.58,63.19 70.05,63.19
  Bottom Layer w0.3: v3(24.725,54.15) v3(25.35,54.15) ; v1(28.075,49.775) v1(28.55,49.775) v1(29,49.775) ; R165.1@51.55,8.675 51.55,8.095 51.905,7.74 52.605,7.74 v3(52.955,8.09)
  Bottom Layer w0.4: v1(33.35,49.725) v1(33.775,49.725) v1(34.2,49.725) ; v3(83.925,8.55) v3@84.175,8.55 ; D1.1@84.575,10.005 84.575,8.95 ; v3(86.55,5.925) 86.55,6.975 v3(84.975,8.55) ; v3@84.175,8.55 v3(84.975,8.55) ; v3@84.175,8.55 84.575,8.95 ; 84.575,8.95 v3(84.975,8.55)
  Bottom Layer w0.6: v3(10.95,36.3) 10.95,36.275 v3(11.4,35.825) ; v3(15.7,38.2) v3(15.7,38.95) ; v3(26.075,59.575) v3(26.075,60.2) v3(26.075,60.825) ; v3(31.85,60.9) v3(32.55,60.9)
  other v3: 27.278,64.4
AGND: C97.1 C100.1 C101.1 C102.1 C103.1 C107.1 C108.1 C109.1 C110.1 C111.1 CN10.2 R83.1 R92.1 R96.1 R103.1 U20.7 U20.13 U22.2 U22.4 U22.5 | length 89.7
  Top Layer w0.3: U22.4@22.95,10.65 U22.5@22.95,9.7 U22.2@25.25,9.7 v3(26.525,9.7) ; v3(26.525,7.975) 27.425,7.975 R103.1@27.45,7.95 ; v3(26.525,11.375) 27.425,11.375 R92.1@27.45,11.35 ; v3(29.625,14.15) 29.625,12.975 CN10.2@30,12.6 ; v3(38.9,9.565) 38.9,11.475 C102.1@39.525,12.1 ; v3(41.05,11.225) 41.4,11.575 U20.7@41.9,11.575 ; C110.1@41.55,7.825 41.575,7.85 v3(42.525,7.85) ; v3(44.175,7.675) C107.1@44.175,8.425 44.275,8.425 44.775,8.925 44.775,9.614 44.575,9.814 U20.13@44.575,10.4 ; C97.1@45.075,17.225 v3(45.075,17.925) ; v3(45.4,7.675) C108.1@45.4,8.425 C109.1@46.3,8.425 ; C103.1@49.075,11.575 v3(49.975,11.575) 50,11.55 R96.1@50,10.475 ; C101.1@49.65,12.7 50.475,12.7 v3(50.45,12.7) 50.825,13.075 R83.1@50.825,14.05 C100.1@49.65,14.05 ; C111.1@49.725,8.5 v3(50.575,8.5)
  Signal Layer 4 w0.3: v3(29.625,14.15) 29.3,14.15 v3(26.525,11.375) v3(26.525,9.7) v3(26.525,7.975) 31.59,7.975 32.455,8.84 38.905,8.84 ; v3(38.9,9.565) 38.905,9.56 38.905,8.84 ; v3(45.075,17.925) 46.93,17.925 ; 38.905,8.84 39.98,8.84 40.97,7.85 v3(42.525,7.85) 42.7,7.675 v3(44.175,7.675) v3(45.4,7.675) 45.4,8.01 45.89,8.5 ; 45.89,8.5 45.89,8.83 44.83,9.89 42.385,9.89 v3(41.05,11.225) 42.055,12.23 42.055,14.89 42.68,15.515 46.215,15.515 46.905,16.205 46.905,17.9 46.93,17.925 ; 45.89,8.5 v3(50.575,8.5) 49.975,9.1 v3(49.975,11.575) 49.975,12.225 v3(50.45,12.7) 50.45,15.495 48.02,17.925 46.93,17.925
AIN_1: R91.2 R94.2 U19.10 | length 2.7
  Top Layer w0.2: R94.2@64.95,10.925 R91.2@64.95,11.975 64.95,12.1 65.575,12.725 U19.10@66.25,12.725
ARD_A0: CN17.1 U13.AC4 | length 56
  Top Layer w0.1: U13.AC4@55.58,26.69 57.003,26.69 57.253,26.94 58.447,26.94 58.872,27.365 59.388,27.365 59.974,26.779 61.103,26.779 62.139,27.815 62.981,27.815 v1(63.281,28.115) v1@63.305,28.139 ; v1@63.281,28.14 v1@63.305,28.14
  Signal Layer 3 w0.1: v1(58.08,15.34) 58.175,15.435 58.175,20.896 60.944,23.665 61.908,23.665 62.38,24.137 62.38,26.81 62.305,26.885 62.305,27.41 63.01,28.115 v1(63.281,28.115)
  Bottom Layer w0.1: CN17.1@38.86,12.165 CN17.1@38.86,11.475 38.86,10.79 39.713,9.937 39.713,8.465 40.209,7.969 40.226,7.969 40.63,7.565 42.174,7.565 42.339,7.4 43.145,7.4 44.255,6.29 48.355,6.29 48.875,6.81 48.875,8.261 50.902,10.288 50.902,12.752 51.065,12.915 52.435,12.915 53.675,11.675 54.89,11.675 55.23,12.015 55.23,12.06 56.11,12.94 57.505,12.94 58.08,13.515 v1(58.08,15.34)
ARD_A1: CN17.2 U13.Y5 | length 37.3
  Top Layer w0.1: v2(53.83,27.44) U13.Y5@54.08,27.19
  Signal Layer 1 w0.1: v2(53.83,27.44) 54.105,27.165 54.105,26.79 54.005,26.69 54.005,25.715 54.28,25.44 54.504,25.44 57.404,22.54 57.506,22.54 58.18,21.866 58.18,20.914 57.575,20.309 57.575,18.91 57.055,18.39 v1(56.955,18.49)
  Signal Layer 2 w0.1: v1(37.55,16.625) 37.823,16.625 38.848,17.65 43.433,17.65 43.733,17.35 49,17.35 49.43,17.78 49.765,17.78 50.26,18.275 52.42,18.275 53.505,17.19 55.69,17.19 55.705,17.175 56.175,17.175 56.6,17.6 56.6,18.49 v1(56.955,18.49)
  Bottom Layer w0.1: CN17.2@36.32,14.904 37.404,14.904 37.55,15.05 v1(37.55,16.625) ; CN17.2@36.33,15.14 CN17.2@36.33,15.59
ARD_A2: CN17.3 U13.U3 | length 37.7
  Top Layer w0.1: v2(52.33,25.94) U13.U3@52.58,26.19
  Signal Layer 1 w0.1: v2(52.33,25.94) 52.33,25.693 53.808,24.215 54.032,24.215 56.508,21.739 v1(56.506,21.265) v1(56.506,21.265)
  Signal Layer 2 w0.1: v1(37.255,18.465) 37.338,18.465 37.973,19.1 43.792,19.1 44.067,19.375 49.475,19.375 50.225,20.125 55.44,20.125 56.506,21.191 v1(56.506,21.265)
  Bottom Layer w0.1: CN17.3@34.15,11 33.78,11.37 CN17.3@33.78,11.475 33.78,15.272 34.983,16.475 36.475,16.475 37.074,17.074 37.074,17.425 36.68,17.82 36.68,18.132 37.013,18.465 v1(37.255,18.465)
ARD_A3: CN17.4 U13.U4 | length 36.4
  Top Layer w0.1: v2(52.33,26.44) U13.U4@52.58,26.69
  Signal Layer 1 w0.1: v2(52.33,26.44) 52.055,26.165 52.055,25.685 53.725,24.015 53.949,24.015 55.955,22.009 55.955,21.415 55.98,21.415 v1(55.988,21.423)
  Signal Layer 2 w0.1: v1(37.28,19.015) 37.606,19.015 38.681,20.09 44.285,20.09 44.775,19.6 49.4,19.6 50.163,20.363 55.312,20.363 56,21.05 56,21.411 v1(55.988,21.423)
  Bottom Layer w0.1: CN17.4@31.24,14.904 33.129,14.904 34.95,16.725 36.375,16.725 36.725,17.075 36.725,17.491 36.48,17.737 36.48,18.215 v1(37.28,19.015)
ARD_A4: SB24.1 U13.W2 | length 65.7
  Top Layer w0.09: U13.W2@53.58,25.69 53.823,25.447 53.83,24.99
  Top Layer w0.1: 53.83,24.99 53.83,24.903 54.583,24.15 54.773,24.15 54.948,23.975 58.892,23.975 59.188,23.679 60.406,23.679 61.144,22.94 62.366,22.94 62.96,23.535 62.96,24.715 63.285,25.04 63.905,25.04 v1(63.98,24.965)
  Signal Layer 2 w0.1: v1(41.13,7.09) 42.175,7.09 42.475,7.39 43.025,7.39 43.19,7.225 46.586,7.225 47.376,8.015 48.225,8.015 48.675,7.565 48.675,6.933 49.133,6.475 62.449,6.475 64.78,8.806 v1(64.78,9.54)
  Bottom Layer w0.1: 35.025,9.29 36.075,10.34 36.075,10.345 36.28,10.55 36.79,10.55 39.075,8.265 39.63,8.265 40.805,7.09 v1(41.13,7.09) ; v1(63.98,24.965) 63.98,24.785 63.78,24.585 63.78,24.09 65.38,22.49 65.38,14.49 63.95,13.06 63.95,10.37 v1(64.78,9.54)
  Bottom Layer w0.3: SB24.1@35.025,9.05 35.025,9.29
ARD_A5: SB26.1 U13.Y9 | length 86.6
  Top Layer w0.1: v2(53.83,29.44) U13.Y9@54.08,29.19
  Signal Layer 1 w0.1: v2(53.83,29.44) 59.042,29.44 59.705,28.777 59.908,28.777 60.75,27.935 60.75,23.715 63.48,20.985 63.48,20.04 63.255,19.815 v1(63.131,19.815)
  Signal Layer 3 w0.1: v1(28.605,4.74) 28.605,8.78 v1(30.025,10.2) ; v1(62.23,8.14) 62.525,7.845 62.525,6.426 61.714,5.615 58.055,5.615 57.68,5.99 57.68,6.436 58.331,7.086 58.331,7.542 57.43,8.443 57.43,14.065 58.48,15.115 58.48,19.005 59.29,19.815 v1(63.131,19.815)
  Bottom Layer w0.1: v1(28.605,4.74) 29.24,5.375 39.295,5.375 39.58,5.09 49.354,5.09 50.564,6.3 54.264,6.3 56.354,8.39 56.646,8.39 56.991,8.735 61.635,8.735 v1(62.23,8.14)
  Bottom Layer w0.3: SB26.1@30.025,9.05 v1(30.025,10.2)
ARD_D0: CN14.1 U13.AA11 | length 94.2
  Top Layer w0.1: U13.AA11@54.58,30.19 v2(54.83,29.94)
  Signal Layer 1 w0.1: v2(54.83,29.94) 60.031,29.94 60.481,29.49 60.481,28.77 60.686,28.565 61.181,28.565 v1@61.48,28.864 ; v1@61.48,28.865 v1(61.53,28.915)
  Signal Layer 3 w0.1: v1(57.83,61.265) 57.83,59.848 57.98,59.698 57.98,49.609 58.339,49.25 61.011,49.25 62,48.261 62,46.377 61.26,45.637 61.26,39.992 62.587,38.665 65.595,38.665 66.525,37.735 66.525,37.389 66.655,37.259 66.655,36.895 66.155,36.395 66.155,36.087 65.809,35.741 65.806,35.741 64.53,34.465 64.53,33.89 61.53,30.89 v1(61.53,28.915)
  Bottom Layer w0.1: CN14.1@26.16,63.164 26.16,67.26 26.305,67.405 30.397,67.405 31.236,66.566 31.236,65.019 31.465,64.79 34.97,64.79 35.235,64.525 35.525,64.525 35.925,64.925 58.755,64.925 59.23,64.45 59.23,61.79 58.705,61.265 v1(57.83,61.265)
ARD_D1: CN14.2 U13.AC13 | length 87.7
  Top Layer w0.1: U13.AC13@55.58,31.19 57.509,31.19 57.709,30.99 58.602,30.99 59.057,30.535 60.438,30.535 60.705,30.802 60.705,31.182 61.53,32.007 61.53,33.015 62.73,34.215 63.455,34.215 63.78,34.54 63.78,35.49 v1(63.28,35.99)
  Signal Layer 2 w0.1: v1(24.88,63.49) 26.755,61.615 27.807,61.615 30.522,58.9 32.092,58.9 32.667,59.475 35.678,59.475 36.448,60.245 37.192,60.245 37.587,59.85 38.505,59.85 40.447,61.792 43.108,61.792 44.409,60.49 46.401,60.49 48.501,62.59 49.314,62.59 50.216,63.492 53.78,63.492 v1(53.93,63.642)
  Signal Layer 3 w0.1: v1(53.93,63.642) v1(53.93,63.642) 54.655,62.915 54.655,61.915 55.18,61.39 55.18,58.648 55.78,58.048 55.78,48.698 59.06,45.418 59.06,36.835 60.555,35.34 62.418,35.34 63.068,35.99 v1(63.28,35.99)
  Bottom Layer w0.1: v1(24.88,63.49) 24.88,61.99 25.395,61.475 27.625,61.475 CN14.2@28.7,60.4 ; CN14.2@28.7,59.735 CN14.2@28.7,60.4 ; CN14.2@28.7,60.51 CN14.2@28.7,60.4
ARD_D2: CN14.3 U13.C8 | length 51.9
  Top Layer w0.1: v1(32.08,64.004) 33.566,64.004 34.405,63.165 v1(34.805,63.165) ; v1(38.668,28.215) 38.668,28.203 38.63,28.165 39.002,28.165 39.652,27.515 40.108,27.515 40.458,27.865 41.03,27.865 41.73,28.565 v4(41.73,28.54) ; U13.C8@45.58,28.69 v2(45.83,28.94)
  Signal Layer 1 w0.1: v4(41.73,28.54) 43.354,28.54 43.754,28.94 v2(45.83,28.94)
  Signal Layer 3 w0.1: v1(34.805,63.165) 34,62.36 34,60.342 32.45,58.792 32.45,52.808 32.5,52.758 32.5,48.719 32.875,48.344 32.875,39.875 33.505,39.245 33.505,34.881 37.375,31.011 37.375,29.214 37.899,28.69 38.135,28.69 38.61,28.215 v1(38.668,28.215)
  Bottom Layer w0.1: CN14.3@31.24,63.164 31.24,63.975 32.051,63.975 v1(32.08,64.004)
ARD_D3: CN14.4 U13.L3 | length 84.6
  Top Layer w0.1: U13.L3@49.54,26.19 U13.L3@49.58,26.19 v2(49.829,26.44) v2@49.829,26.48
  Signal Layer 1 w0.1: v2@49.829,26.48 49.796,26.447 49.796,25.809 49.855,25.75 49.855,23.415 v1(49.93,23.34)
  Signal Layer 2 w0.1: v1(38.055,21.34) 38.08,21.34 38.105,21.365 38.33,21.14 39.11,21.14 39.4,21.14 39.605,21.345 39.61,21.345 39.83,21.565 40.063,21.565 40.338,21.84 45.91,21.84 46.949,20.801 48.851,20.801 49.455,21.405 49.455,22.915 49.88,23.34 v1(49.93,23.34)
  Signal Layer 3 w0.1: v1(27.75,64.925) 27.75,58.911 23.9,55.061 23.9,47.415 28.262,43.053 28.262,42.612 27.7,42.05 27.7,40.101 26.9,39.301 26.9,37.659 26.275,37.034 26.275,33.353 27.13,32.498 27.13,31.391 26.275,30.536 26.275,28.228 29.138,25.365 31.541,25.365 35.416,21.49 37.905,21.49 v1(38.055,21.34)
  Bottom Layer w0.1: v1(27.75,64.925) 27.75,63.025 27.9,62.875 27.9,62.872 28.747,62.025 29.762,62.025 30.423,61.364 33.456,61.364 33.78,61.04 CN14.4@33.78,59.735
ARD_D4: CN14.5 U13.Y15 | length 71.3
  Top Layer w0.1: U13.Y15@54.08,32.19 v2(54.33,31.94) ; v4(61.43,31.465) 61.73,31.765 61.73,32.932 62.813,34.015 63.538,34.015 63.98,34.457 63.98,35.59 63.776,35.794 63.776,36.011 v1(63.781,36.016)
  Signal Layer 1 w0.1: v2(54.33,31.94) 54.43,32.04 60.055,32.04 60.63,31.465 v4(61.43,31.465)
  Signal Layer 2 w0.1: v1(41.655,61.39) 41.857,61.592 43.025,61.592 44.327,60.29 46.483,60.29 48.583,62.39 49.397,62.39 50.299,63.292 54.232,63.292 v1(54.53,63.59)
  Signal Layer 3 w0.1: v1(54.53,63.59) 54.855,63.265 54.855,61.998 55.38,61.473 55.38,58.731 55.98,58.131 55.98,48.781 59.26,45.501 59.26,36.918 60.638,35.54 62.335,35.54 63.135,36.34 63.455,36.34 v1(63.781,36.016)
  Bottom Layer w0.1: CN14.5@36.32,63.164 36.32,64.125 40.075,64.125 40.742,63.458 40.742,61.753 41.105,61.39 v1(41.655,61.39)
ARD_D5: CN14.6 U13.J2 | length 79.2
  Top Layer w0.09: 48.28,23.227 48.525,23.472 48.525,24.184 48.725,24.384 48.725,24.827 48.58,24.972 U13.J2@48.58,25.69
  Top Layer w0.1: v1(39.83,22.615) 41.113,22.615 41.883,21.845 43.276,21.845 43.671,21.45 47.262,21.45 48.005,22.193 48.005,22.952 48.28,23.227
  Signal Layer 3 w0.1: v1(29.225,65) 29.225,64.215 28.475,63.465 28.475,63.228 28.2,62.953 28.2,58.725 26.9,57.425 26.9,45.9 29.375,43.425 29.375,41.171 29.205,41.001 29.205,39.38 28.18,38.355 28.18,31.007 28.68,30.507 28.68,29.273 31.078,26.875 31.87,26.875 32.255,26.49 32.255,25.834 35.799,22.29 39.375,22.29 39.7,22.615 v1(39.83,22.615)
  Bottom Layer w0.1: v1(29.225,65) 29.225,63.7 30.06,62.865 30.335,62.865 30.582,62.618 30.582,61.882 30.7,61.764 34.131,61.764 36.645,59.25 38.375,59.25 CN14.6@38.86,59.735
ARD_D6: CN14.7 U13.AA9 | length 65.7
  Top Layer w0.09: U13.AA9@54.58,29.19 54.83,28.94 55.331,28.94
  Top Layer w0.1: 55.331,28.941 55.47,28.941 55.474,28.945 58.102,28.945 58.312,28.735 59.061,28.735 v1(59.231,28.565)
  Signal Layer 2 w0.1: v1(42.33,61.242) 42.33,61.29 43.044,61.29 44.244,60.09 46.566,60.09 48.666,62.19 49.48,62.19 50.382,63.092 54.532,63.092 v1(55.055,63.615)
  Signal Layer 3 w0.1: v1(55.055,63.615) 55.055,62.081 55.58,61.556 55.58,58.814 56.18,58.214 56.18,48.864 59.46,45.584 59.46,37.001 60.721,35.74 62.252,35.74 63.052,36.54 63.751,36.54 64.131,36.161 64.131,35.871 64.13,35.87 64.13,34.065 59.705,29.64 59.705,29.09 59.231,28.616 v1(59.231,28.565)
  Bottom Layer w0.1: CN14.7@41.4,63.164 41.4,62.42 42.33,61.49 v1(42.33,61.242)
ARD_D7: CN14.8 U13.B9 | length 52.4
  Top Layer w0.1: v1(39.78,29.09) 39.83,29.04 40.06,29.04 40.41,28.69 40.7,28.69 41.05,29.04 42.644,29.04 42.769,28.915 43.391,28.915 43.666,29.19 U13.B9@45.08,29.19
  Signal Layer 3 w0.1: v1(36.4,61.005) 35.025,59.63 35.025,54.154 34.725,53.854 34.725,49.475 34.5,49.25 34.5,43.503 34.23,43.233 34.23,40.54 34.425,40.345 34.425,35.331 39.164,30.592 39.164,29.879 39.78,29.262 v1(39.78,29.09)
  Bottom Layer w0.1: v1(36.4,61.005) 36.411,60.994 36.978,60.994 37.65,61.666 37.65,63.026 37.949,63.325 38.636,63.325 39.125,62.836 39.125,61.57 40.83,59.865 43.811,59.865 CN14.8@43.94,59.736
ARD_D8: CN13.1 U13.T4 | length 120
  Top Layer w0.1: v2(51.83,26.44) U13.T4@52.08,26.69
  Signal Layer 1 w0.1: v2(51.83,26.44) 51.83,25.627 53.947,23.51 53.947,22.756 54.388,22.315 55.366,22.315 55.63,22.051 55.63,21.679 55.45,21.499 55.45,19.78 55.73,19.5 55.875,19.5 56.005,19.37 56.005,18.955 v1(54.85,17.8)
  Signal Layer 2 w0.1: v1(25.33,64.065) 25.33,63.34 26.855,61.815 27.89,61.815 30.605,59.1 32.009,59.1 32.584,59.675 35.595,59.675 36.405,60.485 37.235,60.485 37.67,60.05 38.422,60.05 40.887,62.515 42.95,62.515 44.575,60.89 46.235,60.89 48.56,63.215 v1(48.93,63.215) ; v1(37.78,17.465) 37.755,17.465 38.745,18.455 44.23,18.455 44.55,18.775 45.5,18.775 46.425,17.85 48.625,17.85 49.412,18.637 49.762,18.637 50.275,19.15 50.275,19.161 50.539,19.425 53,19.425 53.675,18.75 53.675,17.765 53.85,17.59 54.64,17.59 v1(54.85,17.8)
  Signal Layer 3 w0.1: v1(25.33,64.065) 25.33,61.335 23.8,59.805 23.8,57.389 23.1,56.689 23.1,47.025 26.7,43.425 26.7,40.533 25.15,38.983 25.15,37.304 25.275,37.179 25.275,27.762 29.397,23.64 31.852,23.64 36.117,19.375 37.52,19.375 38.13,18.765 38.13,17.845 37.78,17.495 v1(37.78,17.465)
  Bottom Layer w0.1: CN13.1@48.004,63.164 48.879,63.164 v1(48.93,63.215)
ARD_D9: CN13.2 U13.Y11 | length 54.7
  Top Layer w0.1: U13.Y11@54.08,30.19 v2(54.33,29.94) ; v4(60.856,29.44) 60.856,29.514 60.905,29.465 61.477,29.465 62.006,29.993 62.006,30.521 62.73,31.245 62.73,31.723 64.98,33.973 64.98,35.195 65.931,36.146 65.931,36.666 v1(66.305,37.04)
  Signal Layer 1 w0.1: v2(54.33,29.94) 54.63,30.24 60.056,30.24 v4(60.856,29.44)
  Signal Layer 3 w0.1: v1(57.38,59.515) 57.58,59.315 57.58,49.443 58.253,48.77 58.986,48.77 60.86,46.896 60.86,39.826 62.721,37.965 63.175,37.965 63.635,38.425 65.552,38.425 66.305,37.672 v1(66.305,37.04)
  Bottom Layer w0.1: CN13.2@50.544,59.735 52.409,59.735 53.805,58.34 56.58,58.34 57.38,59.14 v1(57.38,59.515)
ARD_D10: CN13.3 U13.A4 | length 79.4
  Top Layer w0.1: v1(36.48,26.765) 36.852,26.765 37.476,26.141 38.335,26.141 38.911,25.565 39.698,25.565 39.849,25.715 41.556,25.715 42.306,26.465 43.375,26.465 43.6,26.69 U13.A4@44.58,26.69
  Signal Layer 3 w0.1: v1@32.172,63.347 v1@32.175,63.35 ; v1(32.18,63.34) 31.405,62.565 31.405,61.554 30.1,60.249 30.1,53.616 30.975,52.741 30.975,48.5 29.75,47.275 29.75,44.956 31.131,43.575 31.131,41.144 31.158,41.117 30.73,40.689 30.73,39.816 31.804,38.742 31.804,36.2 31.525,35.921 31.525,32.84 32.499,31.866 33.479,31.866 34.35,30.995 34.35,29.38 36.255,27.475 36.255,26.99 v1(36.48,26.765)
  Bottom Layer w0.1: v1(32.18,63.34) 32.244,63.34 33.42,62.164 34.296,62.164 34.896,61.565 36.983,61.565 37.25,61.832 37.25,63.192 37.783,63.725 39.75,63.725 39.909,63.725 40.342,63.292 40.342,60.977 41.054,60.265 42.73,60.265 42.98,60.515 42.98,61.023 43.422,61.465 52.13,61.465 53.084,62.419 CN13.3@53.084,63.164
ARD_D11: CN13.4 U13.C6 | length 79.3
  Top Layer w0.09: 44.305,27.44 45.33,27.44 U13.C6@45.58,27.69
  Top Layer w0.1: v1(37.706,26.691) 37.706,26.614 38.429,26.614 39.077,25.965 39.533,25.965 39.683,26.115 41.391,26.115 42.439,27.163 42.698,27.163 42.975,27.44 44.305,27.44
  Signal Layer 3 w0.1: v1(32.975,62.114) 33,62.089 33,60.255 30.5,57.755 30.5,53.781 31.75,52.531 31.75,48.494 32.247,47.997 32.247,41.811 32.25,41.809 32.25,41.643 31.13,40.523 31.13,39.982 32.204,38.908 32.204,36.034 31.925,35.755 31.925,33.006 32.665,32.266 33.981,32.266 35.45,30.796 35.45,29.131 36.955,27.627 36.955,26.945 37.16,26.74 37.658,26.74 v1(37.706,26.691)
  Bottom Layer w0.1: v1(32.975,62.114) 33.031,62.114 33.181,61.964 34.214,61.964 34.813,61.365 37.066,61.365 37.45,61.749 37.45,63.109 37.866,63.525 38.719,63.525 39.325,62.919 39.325,61.711 40.971,60.065 42.905,60.065 43.18,60.34 43.18,60.94 43.505,61.265 54.78,61.265 55.624,60.421 CN13.4@55.624,59.735
ARD_D12: CN13.5 U13.A3 | length 91.4
  Top Layer w0.1: v1(35.53,26.965) 35.53,26.99 35.58,27.04 35.585,27.04 36.719,25.906 37.146,25.906 37.31,25.741 38.169,25.741 38.746,25.165 39.864,25.165 40.014,25.315 42.25,25.315 42.875,25.94 43.416,25.94 43.666,26.19 U13.A3@44.58,26.19
  Signal Layer 3 w0.1: v1(30.8,64.96) 30.925,64.835 30.925,61.639 29.7,60.414 29.7,53.45 30.575,52.575 30.575,48.709 29.35,47.484 29.35,44.674 30.199,43.825 30.202,43.825 30.7,43.327 30.7,41.224 30.33,40.854 30.33,39.651 31.404,38.576 31.404,36.366 31.125,36.086 31.125,32.674 32.334,31.466 33.314,31.466 33.95,30.829 33.95,29.214 35.53,27.635 v1(35.53,26.965)
  Bottom Layer w0.1: v1(30.8,64.96) 30.8,64.875 31.085,64.59 32.825,64.59 33.73,63.685 33.73,63.014 34.979,61.765 36.9,61.765 37.05,61.915 37.05,63.275 37.7,63.925 37.925,63.925 39.992,63.925 40.542,63.375 40.542,61.06 41.137,60.465 42.647,60.465 42.78,60.598 42.78,61.106 43.339,61.665 52.047,61.665 52.255,61.873 52.255,64.35 52.47,64.565 57.455,64.565 58.164,63.856 CN13.5@58.164,63.164
ARD_D13: CN13.6 SB6.1 U13.B4 | length 55.9
  Top Layer w0.09: 44.28,26.44 44.83,26.44 U13.B4@45.08,26.69
  Top Layer w0.1: v1(42.555,26.115) 42.555,26.14 43.333,26.14 43.633,26.44 44.28,26.44
  Signal Layer 2 w0.1: v1(42.555,26.115) 43.347,26.115 44.222,26.99 47.573,26.99 48.248,27.665 49.435,27.665 50.11,26.99 51.782,26.99 54.15,29.358 54.15,30.175 57.24,33.265 62.33,33.265 v1(62.48,33.115)
  Bottom Layer w0.1: 60.55,57.4 60.55,56.7 60.1,56.25 60.1,54.025 59.2,53.125 59.2,44.625 60.725,43.1 60.725,33.57 61.18,33.115 v1(62.48,33.115)
  Bottom Layer w0.3: CN13.6@60.704,59.735 60.704,57.546 SB6.1@60.725,57.525
ARD_D14: CN2.3 CN13.9 R166.2 SB23.1 U13.AB19 | length 150.2
  Top Layer w0.1: CN2.3@29.91,66.23 30.025,66.23 31.33,64.925 33.472,64.925 34.122,64.275 37.967,64.275 38.65,63.592 42.222,63.592 43.814,62 55.074,62 55.339,62.265 v1(56.78,62.265) ; U13.AB19@55.08,34.19 55.355,33.915 56.005,33.915 v4(56.505,34.415)
  Signal Layer 1 w0.1: v4(56.505,34.415) 56.505,34.83 59.515,37.84 60.205,37.84 60.345,37.7 63.515,37.7 v1(63.58,37.765)
  Signal Layer 3 w0.1: v1(36.425,10.2) 38.175,8.45 v1(38.175,4.69) ; v1(56.78,62.265) 56.78,59.311 57.38,58.711 57.38,49.361 58.171,48.57 58.903,48.57 60.66,46.814 60.66,38.566 61.686,37.54 63.355,37.54 v1(63.58,37.765) 64.471,37.765 64.931,38.225 65.469,38.225 65.955,37.739 65.955,36.17 65.726,35.941 65.723,35.941 64.33,34.548 64.33,33.973 60.481,30.124 60.481,28.739 60.88,28.34 60.88,24.464 57.575,21.159 57.575,16.506 57.03,15.961 57.03,8.065 v1(57.781,7.314) v1@57.666,7.314
  Bottom Layer w0.1: v1(38.175,4.69) 49.52,4.69 50.73,5.9 55.468,5.9 56.883,7.315 v1@57.78,7.315 ; v1(56.78,62.265) 56.78,61.715 57.58,60.915 58.68,60.915 59.43,61.665 62.005,61.665 62.83,60.84 63.805,60.84 66.129,63.164 CN13.9@68.324,63.164
  Bottom Layer w0.3: SB23.1@36.425,9.05 36.425,9.325 ; v1(36.425,10.2) 36.425,9.325 ; R166.2@37.65,8.45 37.65,9.1 37.425,9.325 36.425,9.325
ARD_D15: CN2.5 CN13.10 R167.2 SB25.1 U13.AA18 | length 167.3
  Top Layer w0.1: CN2.5@32.45,66.23 34.205,64.475 38.05,64.475 38.733,63.792 42.308,63.792 43.85,62.25 54.65,62.25 55.63,63.23 v1(55.63,63.615) ; U13.AA18@54.58,33.69 v2(54.83,33.94) ; v1(62.156,7.564) 61.18,8.54 61.18,9.265 60.425,10.02 60.425,16.895 62.13,18.6 v1(63.025,18.6)
  Signal Layer 1 w0.1: v2(54.83,33.94) 56.419,33.94 56.78,34.301 56.78,34.765 58.88,36.865 v1(60.305,36.865)
  Signal Layer 2 w0.1: v1(55.63,63.615) 55.857,63.842 60.792,63.842 61.1,64.15 62.325,64.15 63.1,63.375 v1(72.589,63.375)
  Signal Layer 3 w0.1: v1(29.53,4.765) 29.53,8.305 v1(31.425,10.2) ; v1(55.63,63.615) 55.68,63.615 55.28,63.215 55.28,62.139 55.78,61.639 55.78,58.896 56.38,58.296 56.38,48.946 59.66,45.666 59.66,37.235 60.03,36.865 v1(60.305,36.865)
  Bottom Layer w0.1: v1(29.53,4.765) 29.94,5.175 39.212,5.175 39.497,4.89 49.437,4.89 50.647,6.1 55.385,6.1 57.82,8.535 61.552,8.535 61.88,8.207 61.88,7.84 v1(62.156,7.564) ; v1(60.305,36.865) 60.525,36.645 60.525,32.428 60.268,32.172 60.268,31.882 60.473,31.677 63.573,31.677 64.525,30.725 64.525,30.104 64.999,29.63 64.999,26.721 64.693,26.415 63.785,26.415 62.88,25.51 62.88,24.382 64.98,22.282 64.98,20.555 v1(63.025,18.6) ; CN13.10@70.864,59.736 71.551,59.736 72.589,60.774 v1(72.589,63.375)
  Bottom Layer w0.3: SB25.1@31.425,9.05 31.425,9.3 ; v1(31.425,10.2) 31.425,9.3 ; R167.2@32.65,8.45 32.65,8.9 32.25,9.3 31.425,9.3
AUDIO_RST: R84.2 U13.Y13 U20.25 | length 42.5
  Top Layer w0.1: R84.2@48.175,15.25 48.175,15.145 48.655,14.665 51.3,14.665 51.59,14.375 51.59,13.575 52.135,13.03 53.255,13.03 54.75,14.525 54.75,15.05 55.1,15.4 55.445,15.4 55.452,15.393 57.309,15.393 v1(57.631,15.715) ; v2(53.83,31.44) U13.Y13@54.08,31.19
  Top Layer w0.3: U20.25@46.075,15.25 R84.2@48.175,15.25
  Signal Layer 1 w0.1: v2(53.83,31.44) 54.305,31.44 54.705,31.84 59.972,31.84 60.622,31.19 61.205,31.19 61.355,31.04 61.355,30.564 61.256,30.465 61.256,30.076 61.95,29.382 v1(62.865,29.382)
  Signal Layer 3 w0.1: v1(57.631,15.715) 57.975,16.059 57.975,20.993 60.847,23.865 61.825,23.865 62.175,24.215 62.175,25.75 61.68,26.245 61.68,27.068 62.155,27.543 62.155,28.672 v1(62.865,29.382)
